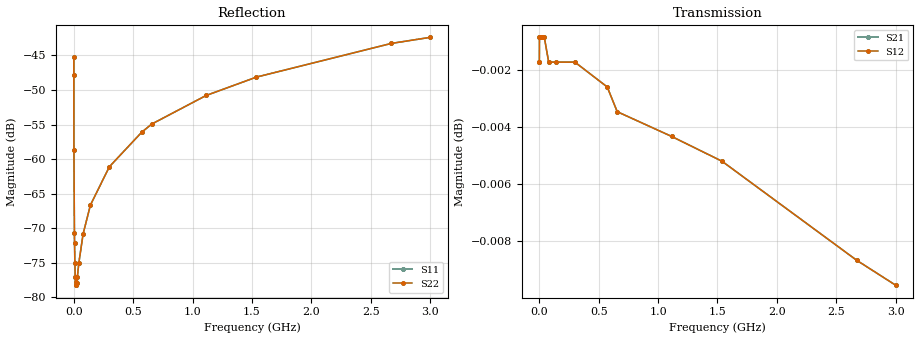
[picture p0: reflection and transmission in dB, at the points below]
! S-Parameter Data Generated by TDK Corporation
! Copyright(C) 2022 TDK Corporation.
! All Rights Reserved.
! TDK P/N: CLLC1AX7S0G105M050AC (Multilayer Ceramic Chip Capacitor)
! Property: C=1uF
! Size(LxWxT): 1.6x0.8x0.5mm
! Model Type: s2p (Touchstone File Format Version 1.0)
! Frequency: DC=Yes Start=0.3MHz Stop=3000MHz 402points Log-sweep
! Model Generated on Apr. 15, 2022
! Port Assignments:
!  1 ---| |--- 2
! Applicable Conditions:
!  Temperature = 25 degC
!  DC Bias Voltage = 0 V
!  Small Signal Operation
! Terms and conditions regarding TDK Simulation Models
! (1)This simulation model is being provided solely for informational purposes. Please refer to the specifications of the products in terms of detailed characteristics of such products.
! (2)In no event shall TDK Corporation of any of its subsidiaries be liable for any loss or damage arising, directly or indirectly,
!  From any information contained in this simulation model, including, but not limited to loss or damages arising from any inaccuracies, omissions or errors in connection with such information.
! (3)Any and all copyrights on this simulation model are owned by TDK Corporation.
!  Duplication or redistribution of this simulation model without prior written permission from TDK Corporation is prohibited.
! (4)This simulation model is subject to any modification or change without any prior notice.
! (5)Neither TDK Corporation nor any of its subsidiaries shall make any warranty, express or implied,
!  Including but not limited to the correctness, implied warranties of merchantability and fitness for a particular purpose with respect to this simulation models.
! (6)The use of this simulation model shall be deemed to have consented to the terms and conditions hereof.
# Hz S MA R 50
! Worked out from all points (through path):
!   401 points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, 300 kHz to 3 GHz, reference 50 ohm
!   highest |S21| = 0.00 dB at 5.586 MHz (marker M1); lowest = 0.0 dB at 3 GHz (marker M2)
!   lowest |S11| = -78.2 dB at 18.08 MHz (marker M3), VSWR 1.00, Z = 50 - j0.00173 ohm
!   |S11| at or under -10 dB: start of sweep to end of sweep
!   |S22| runs from -78.2 to -42.4 dB; largest |S21 - S12| = 0
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300000  0.005449 -87.9  0.9998 0.3  0.9998 0.3  0.005449 -87.9
404689  0.004046 -87.7  0.9998 0.2  0.9998 0.2  0.004046 -87.7
1403210  0.001162 -84.1  0.9999 0.1  0.9999 0.1  0.001162 -84.1
5586260  0.0002941 -67.8  0.9999 0.0  0.9999 0.0  0.0002941 -67.8
6563280  0.0002464 -63.1  0.9999 0.0  0.9999 0.0  0.0002464 -63.1
9270890  0.0001778 -50.0  0.9999 0.0  0.9999 0.0  0.0001778 -50.0
1.25061e7  0.0001403 -33.8  0.9999 0.0  0.9999 0.0  0.0001403 -33.8
1.46934e7  0.0001292 -23.2  0.9999 0.0  0.9999 0.0  0.0001292 -23.2
1.80768e7  0.0001227 -8.1  0.9999 0.0  0.9999 0.0  0.0001227 -8.1
2.07549e7  0.0001239 0.9  0.9999 -0.0  0.9999 -0.0  0.0001239 0.9
2.32874e7  0.0001265 9.0  0.9999 -0.0  0.9999 -0.0  0.0001265 9.0
3e7  0.0001401 23.8  0.9999 -0.0  0.9999 -0.0  0.0001401 23.8
4.23761e7  0.0001765 39.9  0.9999 -0.0  0.9999 -0.0  0.0001765 39.9
7.8908e7  0.0002885 56.9  0.9998 -0.0  0.9998 -0.0  0.0002885 56.9
1.40321e8  0.0004653 66.1  0.9998 -0.0  0.9998 -0.0  0.0004653 66.1
3e8  0.000881 73.7  0.9998 -0.0  0.9998 -0.0  0.000881 73.7
5.71638e8  0.001563 77.8  0.9997 -0.1  0.9997 -0.1  0.001563 77.8
6.56328e8  0.001792 78.5  0.9996 -0.1  0.9996 -0.1  0.001792 78.5
1.11461e9  0.002885 80.6  0.9995 -0.2  0.9995 -0.2  0.002885 80.6
1.53858e9  0.003919 81.6  0.9994 -0.2  0.9994 -0.2  0.003919 81.6
2.67375e9  0.006864 81.6  0.999 -0.4  0.999 -0.4  0.006864 81.6
3e9  0.007592 81.6  0.9989 -0.4  0.9989 -0.4  0.007592 81.6
